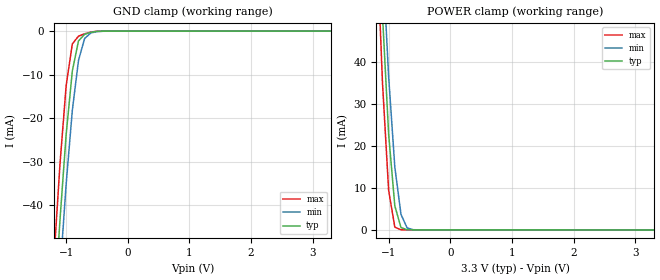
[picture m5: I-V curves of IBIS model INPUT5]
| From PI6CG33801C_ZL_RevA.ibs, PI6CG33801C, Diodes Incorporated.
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[Model] INPUT5
Model_type Input
Vinl = 825mV
Vinh = 2.75V
| variable   typ   min   max
C_comp   0.623pF   0.622pF   0.624pF
[Voltage Range]   3.3V   3.135V   3.465V
[GND Clamp Reference]   0.000V   0.000V   0.000V
[POWER Clamp Reference]   3.3V   3.135V   3.465V
[temperature range]   25   85   -40
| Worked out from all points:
|   GND clamp passes 1 mA (typ) near -0.72 V on its own axis
|   POWER clamp passes 1 mA (typ) near -0.81 V on its own axis
[GND Clamp]
| Voltage   I(typ)   I(min)   I(max)
-3.3V     -806mA     -784mA     -851mA
-1.2V     -65.6mA    -77.9mA    -52.7mA
-1.1V     -43.3mA    -55.5mA    -30.5mA
-1V       -23.7mA    -35.1mA    -12.5mA
-900mV    -9.15mA    -18.2mA    -2.93mA
-800mV    -2.24mA    -6.71mA    -1.13mA
-700mV    -702uA     -1.66mA    -594uA
-600mV    -266uA     -405uA     -185uA
-500mV    -41.5uA    -86.2uA    -13.4uA
3.3V      27.3uA     28.7uA     25.2uA
[POWER Clamp]   |Note: Vtable = Vcc - Voutput
| Voltage   I(typ)   I(min)   I(max)
-3.3V     1.03A      982mA      1.09A
-1.2V     86.4mA     99mA       71.7mA
-1.1V     51.3mA     65.5mA     35.1mA
-1V       22.8mA     36.5mA     9.4mA
-900mV    5.73mA     15mA       645uA
-800mV    550uA      3.69mA     14.4uA
-700mV    24.5uA     448uA      5.4uA
-600mV    5.4uA      31.8uA     4.58uA
3.3V      -27.3uA    -28.7uA    -25.2uA
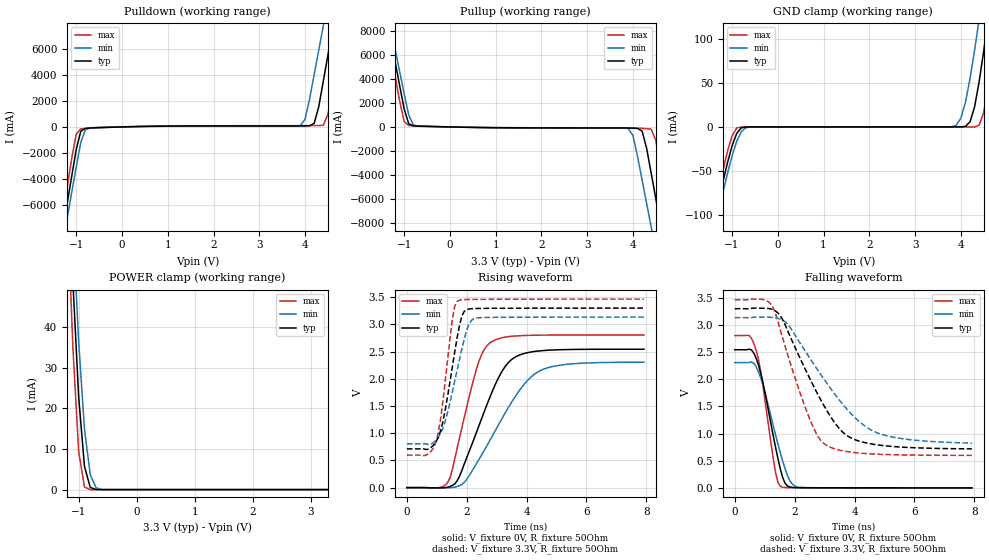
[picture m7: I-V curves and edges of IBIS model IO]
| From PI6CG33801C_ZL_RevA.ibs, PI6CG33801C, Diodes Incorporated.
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[Model]  IO
Model_type  I/O
Vinl = 825mV
Vinh = 2.75V
Vmeas = 1.6v
Vref = 0v
Rref = 50
|Variable   typ   min   max
C_comp   3.27p   3.25p  3.29p
|Variable   typ   min   max
[Voltage Range]   3.3   3.135   3.465
[Temperature Range]   25   85   -40
[GND Clamp Reference]   0   0   0
[POWER Clamp Reference]   3.3   3.135   3.465
[Pullup Reference]   3.3   3.135   3.465
[Pulldown Reference]   0   0   0
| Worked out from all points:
|   slope of the pulldown table from 0 to 0.495 V, typ, clamps not added: 12.4 ohm
|   slope of the pullup table from 0 to 0.495 V, typ, clamps not added: 13.5 ohm
|   GND clamp passes 1 mA (typ) near -0.79 V on its own axis
|   POWER clamp passes 1 mA (typ) near -0.81 V on its own axis
|   falling waveform, V_fixture 0V, R_fixture 50Ohm: 20-80 % time 554ps typ, 652ps min, 448ps max; typ from 2.54 V to 0 V
|   falling waveform, V_fixture 3.3V, R_fixture 50Ohm: 20-80 % time 1.44ns typ, 1.85ns min, 1.05ns max; typ from 3.3 V to 0.718 V
|   rising waveform, V_fixture 0V, R_fixture 50Ohm: 20-80 % time 1.11ns typ, 1.49ns min, 749ps max; typ from 0 V to 2.54 V
|   rising waveform, V_fixture 3.3V, R_fixture 50Ohm: 20-80 % time 479ps typ, 584ps min, 375ps max; typ from 0.712 V to 3.3 V
[GND Clamp]
| Voltage   I(typ)   I(min)   I(max)
-3.3V     -611mA     -617mA     -607mA
-1.5V     -134mA     -146mA     -123mA
-1.4V     -110mA     -121mA     -97.5mA
-1.3V     -85.5mA    -97.3mA    -72.8mA
-900mV    -7.54mA    -16.5mA    -1.27mA
-600mV    -1.35uA    -74.3uA    -1.53nA
3.9V      428nA      1.92mA     13.1pA
4.2V      5.72mA     54.7mA     350nA
4.4V      51.3mA     122mA      2.02mA
4.6V      125mA      199mA      47.1mA
4.8V      208mA      279mA      129mA
6.6V      1.02A      1.05A      1A
[POWER Clamp]   |Note: Vtable = Vcc - Voutput
| Voltage   I(typ)   I(min)   I(max)
-3.3V     1.02A      977mA      1.08A
-1.2V     86.3mA     99mA       71.7mA
-1.1V     51.3mA     65.5mA     35.1mA
-1V       22.8mA     36.4mA     9.39mA
-900mV    5.72mA     14.9mA     638uA
-800mV    544uA      3.68mA     8.25uA
-700mV    18.7uA     441uA      62.5nA
-600mV    428nA      26.6uA     460pA
3.3V      -9.9pA     -97pA      -9.41pA
[Pulldown]   |Note: Vtable = Vcc - Voutput
| Voltage   I(typ)   I(min)  I(max)
-3.3V     -50.1A     -48.7A     -52.2A
-1.3V     -8.03A     -9.02A     -6.94A
-1V       -1.74A     -3.09A     -552mA
-900mV    -332mA     -1.18A     -150mA
-700mV    -81.5mA    -77.7mA    -95.7mA
3.9V      79.7mA     108mA      94.5mA
4.2V      272mA      4.04A      101mA
4.4V      3.54A      7.79A      134mA
4.6V      7.51A      11.6A      3A
4.8V      11.5A      15.3A      7.24A
4.9V      13.5A      17.2A      9.36A
6.6V      61.5A      64A        58.9A
[Pullup]   |Note: Vtable = Vcc - Voutput
| Voltage   I(typ)   I(min)  I(max)
-3.3V     61.5A      57.7A      66.1A
-1.4V     9.45A      10.3A      8.55A
-1.3V     7.46A      8.41A      6.43A
-1V       1.51A      2.77A      448mA
-900mV    261mA      998mA      115mA
3.9V      -88.7mA    -144mA     -102mA
4.2V      -354mA     -4.42A     -124mA
4.4V      -3.89A     -8.37A     -189mA
4.6V      -8.09A     -12.3A     -3.32A
4.8V      -12.3A     -16.3A     -7.8A
4.9V      -14.4A     -18.3A     -10.1A
6.6V      -50.2A     -52.1A     -48.4A
[Falling Waveform]
V_fixture = 0V
V_fixture_min = 0V
V_fixture_max = 0V
R_fixture = 50Ohm
C_fixture = 0F
|   Time   V(typ)   V(min)   V(max)
0s        2.544V     2.307V     2.805V
480ps     2.554V     2.31V      2.807V
720ps     2.378V     2.226V     2.521V
880ps     2.086V     2.006V     2.096V
1.36ns    753.3mV    979.6mV    287mV
1.52ns    351.2mV    646.9mV    29.44mV
1.6ns     190.7mV    494.3mV    9.999mV
1.76ns    34.87mV    229.1mV    4.613mV
2.08ns    4.163mV    16.71mV    2.116mV
7.92ns    24.6uV     67.29uV    6.417uV
[Falling Waveform]
V_fixture = 3.3V
V_fixture_min = 3.135V
V_fixture_max = 3.465V
R_fixture = 50Ohm
C_fixture = 0F
|   Time   V(typ)   V(min)   V(max)
0s        3.3V       3.135V     3.465V
960ps     3.308V     3.143V     3.468V
1.28ns    3.281V     3.138V     3.322V
1.76ns    2.902V     3.015V     2.466V
2.4ns     2.133V     2.48V      1.415V
2.72ns    1.778V     2.212V     1.005V
3.04ns    1.457V     1.955V     790.3mV
3.76ns    957.9mV    1.442V     667.4mV
4.72ns    795.3mV    1.022V     621.1mV
7.92ns    717.9mV    824.9mV    598mV
[Rising Waveform]
V_fixture = 0V
V_fixture_min = 0V
V_fixture_max = 0V
R_fixture = 50Ohm
C_fixture = 0F
|   Time   V(typ)   V(min)   V(max)
0s        0V         0V         0V
1.36ns    6.614mV    -3.444mV   91.17mV
1.68ns    124.8mV    20.42mV    727.6mV
2.32ns    1.008V     436.8mV    2.17V
2.56ns    1.36V      660.3mV    2.515V
2.8ns     1.697V     894.7mV    2.671V
3.44ns    2.327V     1.517V     2.778V
4.4ns     2.511V     2.134V     2.802V
5.52ns    2.54V      2.276V     2.805V
7.92ns    2.544V     2.306V     2.805V
[Rising Waveform]
V_fixture = 3.3V
V_fixture_min = 3.135V
V_fixture_max = 3.465V
R_fixture = 50Ohm
C_fixture = 0F
|   Time   V(typ)   V(min)   V(max)
0s        712.3mV    806.6mV    597.1mV
640ps     700.8mV    804.9mV    595.7mV
960ps     830.7mV    862.9mV    817.9mV
1.2ns     1.203V     1.088V     1.567V
1.52ns    2.221V     1.759V     3.098V
1.68ns    2.757V     2.164V     3.423V
1.92ns    3.242V     2.735V     3.456V
2.08ns    3.284V     3.012V     3.459V
2.32ns    3.293V     3.118V     3.461V
7.92ns    3.3V       3.135V     3.465V
[Ramp]
|   typ   min   max
dV/dt_r   1.53/1.11E-12   1.39/1.50E-12   1.69/0.75E-12
dV/dt_f   1.34/1.44E-12   1.39/1.86E-12   1.72/1.05E-12
R_load =   50.0000
